VERSION 5.8 ;
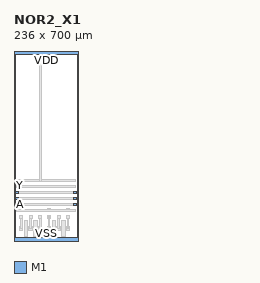
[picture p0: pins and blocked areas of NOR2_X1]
MACRO NOR2_X1
  CLASS CORE ;
  ORIGIN 0 0 ;
  SIZE 236 BY 700 ;
  SITE ICPS2023_5_ROW700 ;
  PIN A
    DIRECTION INPUT ;
    USE SIGNAL ;
    PORT
      LAYER M1 ;
        RECT 5 130 15 140 ;
        RECT 221 130 231 140 ;
    END
  END A
  PIN B
    DIRECTION INPUT ;
    USE SIGNAL ;
    PORT
      LAYER M1 ;
        RECT 5 152 15 162 ;
        RECT 221 152 231 162 ;
    END
  END B
  PIN Y
    DIRECTION OUTPUT ;
    USE SIGNAL ;
    PORT
      LAYER M1 ;
        RECT 5 174 15 184 ;
        RECT 221 174 231 184 ;
    END
  END Y
  PIN VDD
    DIRECTION INOUT ;
    USE POWER ;
    PORT
      LAYER M1 ;
        RECT 0 688 236 700 ;
    END
  END VDD
  PIN VSS
    DIRECTION INOUT ;
    USE GROUND ;
    PORT
      LAYER M1 ;
        RECT 0 0 236 12 ;
    END
  END VSS
  OBS
    LAYER M1 ;
      RECT 20 39.5 33 52.5 ;
      RECT 55 39.5 68 52.5 ;
      RECT 90 39.5 103 52.5 ;
      RECT 37.5 16 50.5 29 ;
      RECT 37.5 63 50.5 76 ;
      RECT 37 16 51 76 ;
      RECT 72.5 16 85.5 29 ;
      RECT 72.5 63 85.5 76 ;
      RECT 72 16 86 76 ;
      RECT 23.5 46 29.5 89 ;
      RECT 21.5 84 31.5 94 ;
      RECT 21.5 174 31.5 184 ;
      RECT 58.5 46 64.5 89 ;
      RECT 56.5 84 66.5 94 ;
      RECT 56.5 196 66.5 206 ;
      RECT 93.5 46 99.5 89 ;
      RECT 91.5 84 101.5 94 ;
      RECT 91.5 218 101.5 228 ;
      RECT 39 130 49 140 ;
      RECT 74 152 84 162 ;
      RECT 123 39.5 136 52.5 ;
      RECT 158 39.5 171 52.5 ;
      RECT 193 39.5 206 52.5 ;
      RECT 140.5 16 153.5 29 ;
      RECT 140.5 63 153.5 76 ;
      RECT 140 16 154 76 ;
      RECT 175.5 16 188.5 29 ;
      RECT 175.5 63 188.5 76 ;
      RECT 175 16 189 76 ;
      RECT 126.5 46 132.5 89 ;
      RECT 124.5 84 134.5 94 ;
      RECT 124.5 108 134.5 118 ;
      RECT 161.5 46 167.5 89 ;
      RECT 159.5 84 169.5 94 ;
      RECT 159.5 174 169.5 184 ;
      RECT 196.5 46 202.5 89 ;
      RECT 194.5 84 204.5 94 ;
      RECT 194.5 108 204.5 118 ;
      RECT 142 130 152 140 ;
      RECT 177 152 187 162 ;
      RECT 10 110 226 116 ;
      RECT 10 132 226 138 ;
      RECT 10 154 226 160 ;
      RECT 10 176 226 182 ;
      RECT 10 198 226 204 ;
      RECT 10 220 226 226 ;
      RECT 126.5 3 132.5 92 ;
      RECT 93.5 220 99.5 697 ;
  END
END NOR2_X1
